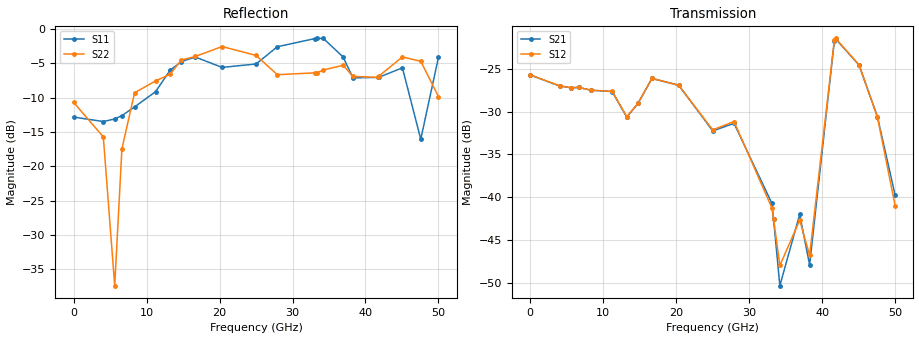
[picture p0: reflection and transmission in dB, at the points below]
!Keysight Technologies,N5245B,MY58422270,A.16.20.02
!Date: Thursday, March 05, 2026 01:34:26
!Correction: S11(C  2-Port  )
!S21(C  2-Port  )
!S12(C  2-Port  )
!S22(C  2-Port  )
!S2P File: Measurements: S11, S21, S12, S22:
# Hz S  dB  R 50
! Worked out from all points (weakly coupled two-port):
!   3201 points, 10 MHz to 50 GHz, reference 50 ohm
!   highest |S21| = -21.52 dB at 41.85 GHz (marker M1); lowest = -50.3 dB at 34.21 GHz (marker M2)
!   lowest |S11| = -16.0 dB at 47.58 GHz (marker M3), VSWR 1.37, Z = 45.4 + j14.5 ohm
!   |S11| at or under -10 dB: start of sweep to 9.801 GHz; 11.44 GHz to 11.86 GHz (420.4 MHz wide, 3.61 % of centre); 46.74 GHz to 48.32 GHz (1.582 GHz wide, 3.33 % of centre)
!   |S22| runs from -37.4 to -2.5 dB; largest |S21 - S12| = 0.009
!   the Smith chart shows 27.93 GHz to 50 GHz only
!   S11 on the Smith chart (normalised r, x): 27.93 GHz: 0.20, +0.56; 33.11 GHz: 0.66, +2.65; 36.92 GHz: 1.53, -1.93; 47.58 GHz: 0.91, +0.29; 50 GHz: 0.54, -1.08
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1e7  -12.82 -3.9  -25.73 6.0  -25.74 9.8  -10.68 30.5
4.071688e9  -13.46 -105.7  -27.04 -152.0  -27.00 -151.8  -15.70 -175.2
5.633875e9  -13.09 -138.5  -27.23 146.0  -27.22 146.1  -37.37 -138.8
6.618053e9  -12.60 -154.9  -27.18 104.0  -27.19 103.9  -17.46 -82.2
8.352081e9  -11.34 169.9  -27.52 31.6  -27.50 31.6  -9.28 -143.7
1.122651e10  -9.12 100.3  -27.67 -71.7  -27.66 -71.8  -7.55 94.4
1.322611e10  -6.00 60.8  -30.66 -120.7  -30.59 -120.7  -6.58 -17.0
1.475705e10  -4.73 13.4  -29.06 -148.4  -29.06 -148.4  -4.50 -88.0
1.667854e10  -4.07 -44.5  -26.14 158.1  -26.13 157.6  -3.99 -141.2
2.034968e10  -5.58 -127.3  -26.94 40.0  -26.94 39.7  -2.54 153.8
2.5005e10  -5.08 170.8  -32.26 -65.8  -32.14 -66.0  -3.83 70.8
2.792629e10  -2.57 119.7  -31.38 -131.9  -31.17 -131.9  -6.64 18.0
3.311275e10  -1.37 39.4  -40.71 13.2  -41.25 14.5  -6.37 -124.5
3.334708e10  -1.36 35.4  -42.59 2.3  -42.54 0.6  -6.37 -129.8
3.420628e10  -1.35 20.8  -50.33 -73.8  -47.97 -69.4  -5.96 -148.4
3.692449e10  -4.04 -37.3  -42.00 99.4  -42.69 98.3  -5.27 157.6
3.828359e10  -7.11 -20.4  -47.90 106.2  -46.77 -79.2  -6.89 134.7
4.167354e10  -7.03 -56.7  -21.75 -61.6  -21.65 -61.9  -7.02 113.9
4.184538e10  -7.01 -56.8  -21.52 -77.6  -21.46 -77.9  -6.84 112.8
4.506349e10  -5.64 -105.4  -24.59 88.0  -24.55 87.7  -4.06 76.3
4.757861e10  -16.04 99.0  -30.60 -13.1  -30.66 -11.9  -4.69 41.9
5e10  -4.13 -78.1  -39.74 -128.3  -40.97 -135.7  -9.82 6.0
